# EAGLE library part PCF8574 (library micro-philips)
I2C-Bus I/O DEVICE

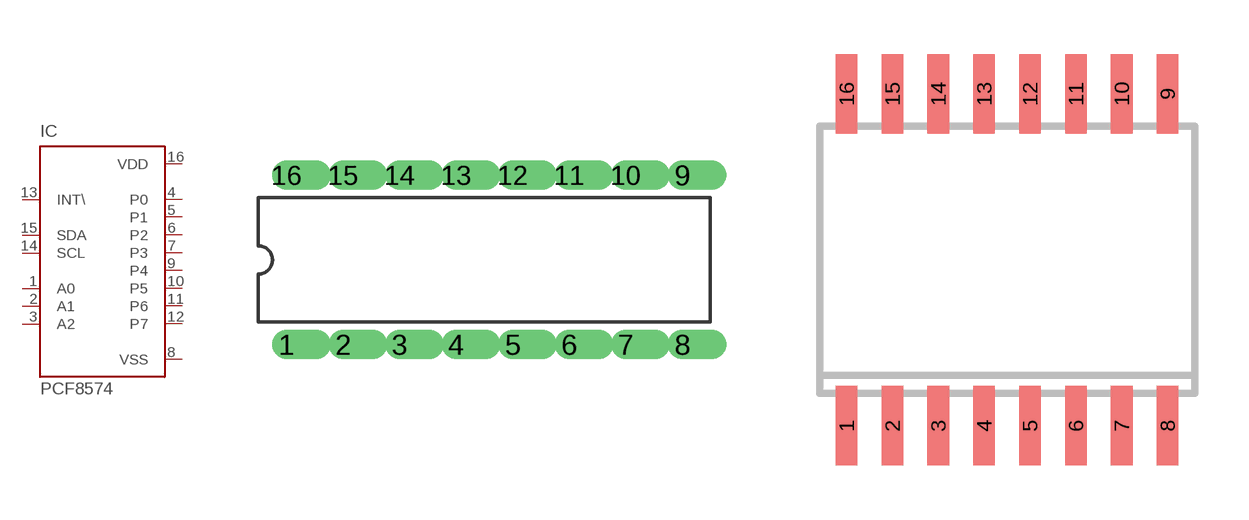
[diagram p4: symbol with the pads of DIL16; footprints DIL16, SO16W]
Designator prefix IC

## PCF8574P  [DIL16]
1  A0  in
2  A1  in
3  A2  in
4  P0
5  P1
6  P2
7  P3
8  VSS  pwr
9  P4
10  P5
11  P6
12  P7
13  INT\  out
14  SCL  in
15  SDA
16  VDD  pwr

## PCF8574T  [SO16W]
Pads as for DIL16

## Footprint DIL16 (pad centres in mm)
Dual In Line
drill 0.813 offset: 1 -8.89,-3.81; 2 -6.35,-3.81; 3 -3.81,-3.81; 4 -1.27,-3.81; 5 1.27,-3.81; 6 3.81,-3.81; 7 6.35,-3.81; 8 8.89,-3.81; 9 8.89,3.81; 10 6.35,3.81; 11 3.81,3.81; 12 1.27,3.81; 13 -1.27,3.81; 14 -3.81,3.81; 15 -6.35,3.81; 16 -8.89,3.81

## Footprint SO16W (pad centres in mm)
Small Outline Package 7.6 x 10.6 mm
smd 0.6 x 2.2: 1 -4.445,-4.6; 2 -3.175,-4.6; 3 -1.905,-4.6; 4 -0.635,-4.6; 5 0.635,-4.6; 6 1.905,-4.6; 7 3.175,-4.6; 8 4.445,-4.6; 9 4.445,4.6; 10 3.175,4.6; 11 1.905,4.6; 12 0.635,4.6; 13 -0.635,4.6; 14 -1.905,4.6; 15 -3.175,4.6; 16 -4.445,4.6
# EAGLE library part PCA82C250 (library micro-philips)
CAN CONTROLLER INTERFACE

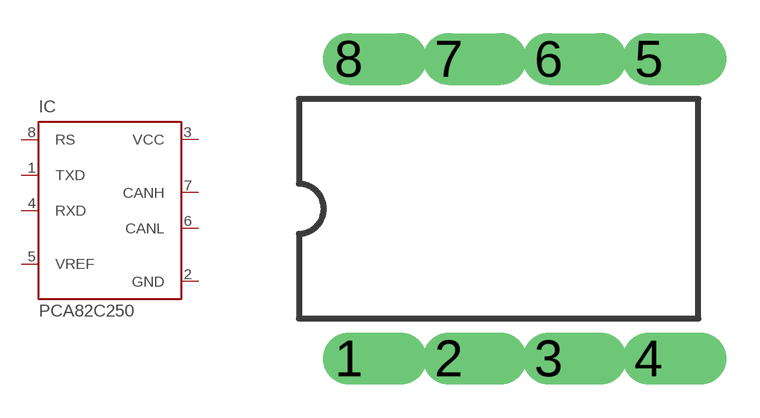
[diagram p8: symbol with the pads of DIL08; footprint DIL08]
Designator prefix IC

## PCA82C250  [DIL08]
1  TXD  in
2  GND  pwr
3  VCC  pwr
4  RXD  out
5  VREF  out
6  CANL
7  CANH
8  RS  in

## Footprint DIL08 (pad centres in mm)
Dual In Line
drill 0.813 offset: 1 -3.81,-3.81; 2 -1.27,-3.81; 3 1.27,-3.81; 4 3.81,-3.81; 5 3.81,3.81; 6 1.27,3.81; 7 -1.27,3.81; 8 -3.81,3.81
